VERSION 5.7 ;
BUSBITCHARS "[]" ;
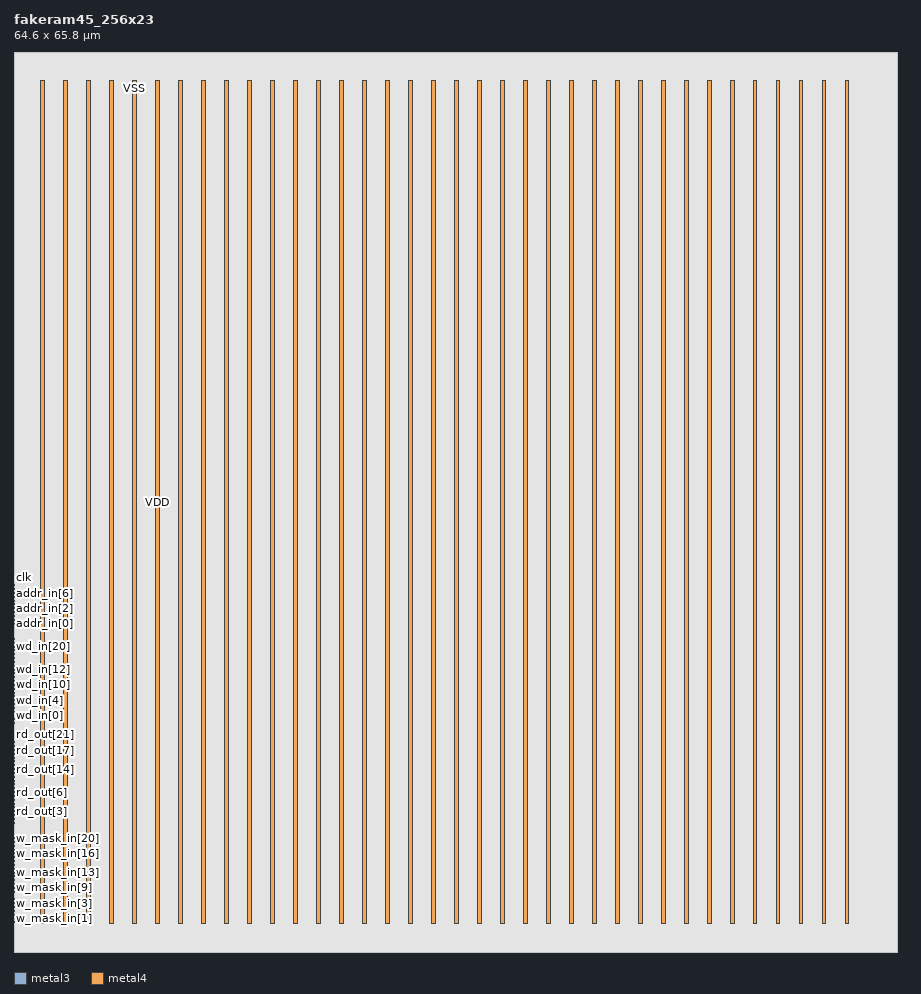
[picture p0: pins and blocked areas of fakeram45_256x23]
MACRO fakeram45_256x23
  FOREIGN fakeram45_256x23 0 0 ;
  SYMMETRY X Y R90 ;
  SIZE 64.600 BY 65.800 ;
  CLASS BLOCK ;
  PIN w_mask_in[0]
    DIRECTION INPUT ;
    USE SIGNAL ;
    SHAPE ABUTMENT ;
    PORT
      LAYER metal3 ;
      RECT 0.000 2.135 0.070 2.205 ;
    END
  END w_mask_in[0]
  PIN w_mask_in[1]
    DIRECTION INPUT ;
    USE SIGNAL ;
    SHAPE ABUTMENT ;
    PORT
      LAYER metal3 ;
      RECT 0.000 2.415 0.070 2.485 ;
    END
  END w_mask_in[1]
  PIN w_mask_in[2]
    DIRECTION INPUT ;
    USE SIGNAL ;
    SHAPE ABUTMENT ;
    PORT
      LAYER metal3 ;
      RECT 0.000 2.695 0.070 2.765 ;
    END
  END w_mask_in[2]
  PIN w_mask_in[3]
    DIRECTION INPUT ;
    USE SIGNAL ;
    SHAPE ABUTMENT ;
    PORT
      LAYER metal3 ;
      RECT 0.000 2.975 0.070 3.045 ;
    END
  END w_mask_in[3]
  PIN w_mask_in[4]
    DIRECTION INPUT ;
    USE SIGNAL ;
    SHAPE ABUTMENT ;
    PORT
      LAYER metal3 ;
      RECT 0.000 3.255 0.070 3.325 ;
    END
  END w_mask_in[4]
  PIN w_mask_in[5]
    DIRECTION INPUT ;
    USE SIGNAL ;
    SHAPE ABUTMENT ;
    PORT
      LAYER metal3 ;
      RECT 0.000 3.535 0.070 3.605 ;
    END
  END w_mask_in[5]
  PIN w_mask_in[6]
    DIRECTION INPUT ;
    USE SIGNAL ;
    SHAPE ABUTMENT ;
    PORT
      LAYER metal3 ;
      RECT 0.000 3.815 0.070 3.885 ;
    END
  END w_mask_in[6]
  PIN w_mask_in[7]
    DIRECTION INPUT ;
    USE SIGNAL ;
    SHAPE ABUTMENT ;
    PORT
      LAYER metal3 ;
      RECT 0.000 4.095 0.070 4.165 ;
    END
  END w_mask_in[7]
  PIN w_mask_in[8]
    DIRECTION INPUT ;
    USE SIGNAL ;
    SHAPE ABUTMENT ;
    PORT
      LAYER metal3 ;
      RECT 0.000 4.375 0.070 4.445 ;
    END
  END w_mask_in[8]
  PIN w_mask_in[9]
    DIRECTION INPUT ;
    USE SIGNAL ;
    SHAPE ABUTMENT ;
    PORT
      LAYER metal3 ;
      RECT 0.000 4.655 0.070 4.725 ;
    END
  END w_mask_in[9]
  PIN w_mask_in[10]
    DIRECTION INPUT ;
    USE SIGNAL ;
    SHAPE ABUTMENT ;
    PORT
      LAYER metal3 ;
      RECT 0.000 4.935 0.070 5.005 ;
    END
  END w_mask_in[10]
  PIN w_mask_in[11]
    DIRECTION INPUT ;
    USE SIGNAL ;
    SHAPE ABUTMENT ;
    PORT
      LAYER metal3 ;
      RECT 0.000 5.215 0.070 5.285 ;
    END
  END w_mask_in[11]
  PIN w_mask_in[12]
    DIRECTION INPUT ;
    USE SIGNAL ;
    SHAPE ABUTMENT ;
    PORT
      LAYER metal3 ;
      RECT 0.000 5.495 0.070 5.565 ;
    END
  END w_mask_in[12]
  PIN w_mask_in[13]
    DIRECTION INPUT ;
    USE SIGNAL ;
    SHAPE ABUTMENT ;
    PORT
      LAYER metal3 ;
      RECT 0.000 5.775 0.070 5.845 ;
    END
  END w_mask_in[13]
  PIN w_mask_in[14]
    DIRECTION INPUT ;
    USE SIGNAL ;
    SHAPE ABUTMENT ;
    PORT
      LAYER metal3 ;
      RECT 0.000 6.055 0.070 6.125 ;
    END
  END w_mask_in[14]
  PIN w_mask_in[15]
    DIRECTION INPUT ;
    USE SIGNAL ;
    SHAPE ABUTMENT ;
    PORT
      LAYER metal3 ;
      RECT 0.000 6.335 0.070 6.405 ;
    END
  END w_mask_in[15]
  PIN w_mask_in[16]
    DIRECTION INPUT ;
    USE SIGNAL ;
    SHAPE ABUTMENT ;
    PORT
      LAYER metal3 ;
      RECT 0.000 6.615 0.070 6.685 ;
    END
  END w_mask_in[16]
  PIN w_mask_in[17]
    DIRECTION INPUT ;
    USE SIGNAL ;
    SHAPE ABUTMENT ;
    PORT
      LAYER metal3 ;
      RECT 0.000 6.895 0.070 6.965 ;
    END
  END w_mask_in[17]
  PIN w_mask_in[18]
    DIRECTION INPUT ;
    USE SIGNAL ;
    SHAPE ABUTMENT ;
    PORT
      LAYER metal3 ;
      RECT 0.000 7.175 0.070 7.245 ;
    END
  END w_mask_in[18]
  PIN w_mask_in[19]
    DIRECTION INPUT ;
    USE SIGNAL ;
    SHAPE ABUTMENT ;
    PORT
      LAYER metal3 ;
      RECT 0.000 7.455 0.070 7.525 ;
    END
  END w_mask_in[19]
  PIN w_mask_in[20]
    DIRECTION INPUT ;
    USE SIGNAL ;
    SHAPE ABUTMENT ;
    PORT
      LAYER metal3 ;
      RECT 0.000 7.735 0.070 7.805 ;
    END
  END w_mask_in[20]
  PIN w_mask_in[21]
    DIRECTION INPUT ;
    USE SIGNAL ;
    SHAPE ABUTMENT ;
    PORT
      LAYER metal3 ;
      RECT 0.000 8.015 0.070 8.085 ;
    END
  END w_mask_in[21]
  PIN w_mask_in[22]
    DIRECTION INPUT ;
    USE SIGNAL ;
    SHAPE ABUTMENT ;
    PORT
      LAYER metal3 ;
      RECT 0.000 8.295 0.070 8.365 ;
    END
  END w_mask_in[22]
  PIN rd_out[0]
    DIRECTION OUTPUT ;
    USE SIGNAL ;
    SHAPE ABUTMENT ;
    PORT
      LAYER metal3 ;
      RECT 0.000 9.415 0.070 9.485 ;
    END
  END rd_out[0]
  PIN rd_out[1]
    DIRECTION OUTPUT ;
    USE SIGNAL ;
    SHAPE ABUTMENT ;
    PORT
      LAYER metal3 ;
      RECT 0.000 9.695 0.070 9.765 ;
    END
  END rd_out[1]
  PIN rd_out[2]
    DIRECTION OUTPUT ;
    USE SIGNAL ;
    SHAPE ABUTMENT ;
    PORT
      LAYER metal3 ;
      RECT 0.000 9.975 0.070 10.045 ;
    END
  END rd_out[2]
  PIN rd_out[3]
    DIRECTION OUTPUT ;
    USE SIGNAL ;
    SHAPE ABUTMENT ;
    PORT
      LAYER metal3 ;
      RECT 0.000 10.255 0.070 10.325 ;
    END
  END rd_out[3]
  PIN rd_out[4]
    DIRECTION OUTPUT ;
    USE SIGNAL ;
    SHAPE ABUTMENT ;
    PORT
      LAYER metal3 ;
      RECT 0.000 10.535 0.070 10.605 ;
    END
  END rd_out[4]
  PIN rd_out[5]
    DIRECTION OUTPUT ;
    USE SIGNAL ;
    SHAPE ABUTMENT ;
    PORT
      LAYER metal3 ;
      RECT 0.000 10.815 0.070 10.885 ;
    END
  END rd_out[5]
  PIN rd_out[6]
    DIRECTION OUTPUT ;
    USE SIGNAL ;
    SHAPE ABUTMENT ;
    PORT
      LAYER metal3 ;
      RECT 0.000 11.095 0.070 11.165 ;
    END
  END rd_out[6]
  PIN rd_out[7]
    DIRECTION OUTPUT ;
    USE SIGNAL ;
    SHAPE ABUTMENT ;
    PORT
      LAYER metal3 ;
      RECT 0.000 11.375 0.070 11.445 ;
    END
  END rd_out[7]
  PIN rd_out[8]
    DIRECTION OUTPUT ;
    USE SIGNAL ;
    SHAPE ABUTMENT ;
    PORT
      LAYER metal3 ;
      RECT 0.000 11.655 0.070 11.725 ;
    END
  END rd_out[8]
  PIN rd_out[9]
    DIRECTION OUTPUT ;
    USE SIGNAL ;
    SHAPE ABUTMENT ;
    PORT
      LAYER metal3 ;
      RECT 0.000 11.935 0.070 12.005 ;
    END
  END rd_out[9]
  PIN rd_out[10]
    DIRECTION OUTPUT ;
    USE SIGNAL ;
    SHAPE ABUTMENT ;
    PORT
      LAYER metal3 ;
      RECT 0.000 12.215 0.070 12.285 ;
    END
  END rd_out[10]
  PIN rd_out[11]
    DIRECTION OUTPUT ;
    USE SIGNAL ;
    SHAPE ABUTMENT ;
    PORT
      LAYER metal3 ;
      RECT 0.000 12.495 0.070 12.565 ;
    END
  END rd_out[11]
  PIN rd_out[12]
    DIRECTION OUTPUT ;
    USE SIGNAL ;
    SHAPE ABUTMENT ;
    PORT
      LAYER metal3 ;
      RECT 0.000 12.775 0.070 12.845 ;
    END
  END rd_out[12]
  PIN rd_out[13]
    DIRECTION OUTPUT ;
    USE SIGNAL ;
    SHAPE ABUTMENT ;
    PORT
      LAYER metal3 ;
      RECT 0.000 13.055 0.070 13.125 ;
    END
  END rd_out[13]
  PIN rd_out[14]
    DIRECTION OUTPUT ;
    USE SIGNAL ;
    SHAPE ABUTMENT ;
    PORT
      LAYER metal3 ;
      RECT 0.000 13.335 0.070 13.405 ;
    END
  END rd_out[14]
  PIN rd_out[15]
    DIRECTION OUTPUT ;
    USE SIGNAL ;
    SHAPE ABUTMENT ;
    PORT
      LAYER metal3 ;
      RECT 0.000 13.615 0.070 13.685 ;
    END
  END rd_out[15]
  PIN rd_out[16]
    DIRECTION OUTPUT ;
    USE SIGNAL ;
    SHAPE ABUTMENT ;
    PORT
      LAYER metal3 ;
      RECT 0.000 13.895 0.070 13.965 ;
    END
  END rd_out[16]
  PIN rd_out[17]
    DIRECTION OUTPUT ;
    USE SIGNAL ;
    SHAPE ABUTMENT ;
    PORT
      LAYER metal3 ;
      RECT 0.000 14.175 0.070 14.245 ;
    END
  END rd_out[17]
  PIN rd_out[18]
    DIRECTION OUTPUT ;
    USE SIGNAL ;
    SHAPE ABUTMENT ;
    PORT
      LAYER metal3 ;
      RECT 0.000 14.455 0.070 14.525 ;
    END
  END rd_out[18]
  PIN rd_out[19]
    DIRECTION OUTPUT ;
    USE SIGNAL ;
    SHAPE ABUTMENT ;
    PORT
      LAYER metal3 ;
      RECT 0.000 14.735 0.070 14.805 ;
    END
  END rd_out[19]
  PIN rd_out[20]
    DIRECTION OUTPUT ;
    USE SIGNAL ;
    SHAPE ABUTMENT ;
    PORT
      LAYER metal3 ;
      RECT 0.000 15.015 0.070 15.085 ;
    END
  END rd_out[20]
  PIN rd_out[21]
    DIRECTION OUTPUT ;
    USE SIGNAL ;
    SHAPE ABUTMENT ;
    PORT
      LAYER metal3 ;
      RECT 0.000 15.295 0.070 15.365 ;
    END
  END rd_out[21]
  PIN rd_out[22]
    DIRECTION OUTPUT ;
    USE SIGNAL ;
    SHAPE ABUTMENT ;
    PORT
      LAYER metal3 ;
      RECT 0.000 15.575 0.070 15.645 ;
    END
  END rd_out[22]
  PIN wd_in[0]
    DIRECTION INPUT ;
    USE SIGNAL ;
    SHAPE ABUTMENT ;
    PORT
      LAYER metal3 ;
      RECT 0.000 16.695 0.070 16.765 ;
    END
  END wd_in[0]
  PIN wd_in[1]
    DIRECTION INPUT ;
    USE SIGNAL ;
    SHAPE ABUTMENT ;
    PORT
      LAYER metal3 ;
      RECT 0.000 16.975 0.070 17.045 ;
    END
  END wd_in[1]
  PIN wd_in[2]
    DIRECTION INPUT ;
    USE SIGNAL ;
    SHAPE ABUTMENT ;
    PORT
      LAYER metal3 ;
      RECT 0.000 17.255 0.070 17.325 ;
    END
  END wd_in[2]
  PIN wd_in[3]
    DIRECTION INPUT ;
    USE SIGNAL ;
    SHAPE ABUTMENT ;
    PORT
      LAYER metal3 ;
      RECT 0.000 17.535 0.070 17.605 ;
    END
  END wd_in[3]
  PIN wd_in[4]
    DIRECTION INPUT ;
    USE SIGNAL ;
    SHAPE ABUTMENT ;
    PORT
      LAYER metal3 ;
      RECT 0.000 17.815 0.070 17.885 ;
    END
  END wd_in[4]
  PIN wd_in[5]
    DIRECTION INPUT ;
    USE SIGNAL ;
    SHAPE ABUTMENT ;
    PORT
      LAYER metal3 ;
      RECT 0.000 18.095 0.070 18.165 ;
    END
  END wd_in[5]
  PIN wd_in[6]
    DIRECTION INPUT ;
    USE SIGNAL ;
    SHAPE ABUTMENT ;
    PORT
      LAYER metal3 ;
      RECT 0.000 18.375 0.070 18.445 ;
    END
  END wd_in[6]
  PIN wd_in[7]
    DIRECTION INPUT ;
    USE SIGNAL ;
    SHAPE ABUTMENT ;
    PORT
      LAYER metal3 ;
      RECT 0.000 18.655 0.070 18.725 ;
    END
  END wd_in[7]
  PIN wd_in[8]
    DIRECTION INPUT ;
    USE SIGNAL ;
    SHAPE ABUTMENT ;
    PORT
      LAYER metal3 ;
      RECT 0.000 18.935 0.070 19.005 ;
    END
  END wd_in[8]
  PIN wd_in[9]
    DIRECTION INPUT ;
    USE SIGNAL ;
    SHAPE ABUTMENT ;
    PORT
      LAYER metal3 ;
      RECT 0.000 19.215 0.070 19.285 ;
    END
  END wd_in[9]
  PIN wd_in[10]
    DIRECTION INPUT ;
    USE SIGNAL ;
    SHAPE ABUTMENT ;
    PORT
      LAYER metal3 ;
      RECT 0.000 19.495 0.070 19.565 ;
    END
  END wd_in[10]
  PIN wd_in[11]
    DIRECTION INPUT ;
    USE SIGNAL ;
    SHAPE ABUTMENT ;
    PORT
      LAYER metal3 ;
      RECT 0.000 19.775 0.070 19.845 ;
    END
  END wd_in[11]
  PIN wd_in[12]
    DIRECTION INPUT ;
    USE SIGNAL ;
    SHAPE ABUTMENT ;
    PORT
      LAYER metal3 ;
      RECT 0.000 20.055 0.070 20.125 ;
    END
  END wd_in[12]
  PIN wd_in[13]
    DIRECTION INPUT ;
    USE SIGNAL ;
    SHAPE ABUTMENT ;
    PORT
      LAYER metal3 ;
      RECT 0.000 20.335 0.070 20.405 ;
    END
  END wd_in[13]
  PIN wd_in[14]
    DIRECTION INPUT ;
    USE SIGNAL ;
    SHAPE ABUTMENT ;
    PORT
      LAYER metal3 ;
      RECT 0.000 20.615 0.070 20.685 ;
    END
  END wd_in[14]
  PIN wd_in[15]
    DIRECTION INPUT ;
    USE SIGNAL ;
    SHAPE ABUTMENT ;
    PORT
      LAYER metal3 ;
      RECT 0.000 20.895 0.070 20.965 ;
    END
  END wd_in[15]
  PIN wd_in[16]
    DIRECTION INPUT ;
    USE SIGNAL ;
    SHAPE ABUTMENT ;
    PORT
      LAYER metal3 ;
      RECT 0.000 21.175 0.070 21.245 ;
    END
  END wd_in[16]
  PIN wd_in[17]
    DIRECTION INPUT ;
    USE SIGNAL ;
    SHAPE ABUTMENT ;
    PORT
      LAYER metal3 ;
      RECT 0.000 21.455 0.070 21.525 ;
    END
  END wd_in[17]
  PIN wd_in[18]
    DIRECTION INPUT ;
    USE SIGNAL ;
    SHAPE ABUTMENT ;
    PORT
      LAYER metal3 ;
      RECT 0.000 21.735 0.070 21.805 ;
    END
  END wd_in[18]
  PIN wd_in[19]
    DIRECTION INPUT ;
    USE SIGNAL ;
    SHAPE ABUTMENT ;
    PORT
      LAYER metal3 ;
      RECT 0.000 22.015 0.070 22.085 ;
    END
  END wd_in[19]
  PIN wd_in[20]
    DIRECTION INPUT ;
    USE SIGNAL ;
    SHAPE ABUTMENT ;
    PORT
      LAYER metal3 ;
      RECT 0.000 22.295 0.070 22.365 ;
    END
  END wd_in[20]
  PIN wd_in[21]
    DIRECTION INPUT ;
    USE SIGNAL ;
    SHAPE ABUTMENT ;
    PORT
      LAYER metal3 ;
      RECT 0.000 22.575 0.070 22.645 ;
    END
  END wd_in[21]
  PIN wd_in[22]
    DIRECTION INPUT ;
    USE SIGNAL ;
    SHAPE ABUTMENT ;
    PORT
      LAYER metal3 ;
      RECT 0.000 22.855 0.070 22.925 ;
    END
  END wd_in[22]
  PIN addr_in[0]
    DIRECTION INPUT ;
    USE SIGNAL ;
    SHAPE ABUTMENT ;
    PORT
      LAYER metal3 ;
      RECT 0.000 23.975 0.070 24.045 ;
    END
  END addr_in[0]
  PIN addr_in[1]
    DIRECTION INPUT ;
    USE SIGNAL ;
    SHAPE ABUTMENT ;
    PORT
      LAYER metal3 ;
      RECT 0.000 24.255 0.070 24.325 ;
    END
  END addr_in[1]
  PIN addr_in[2]
    DIRECTION INPUT ;
    USE SIGNAL ;
    SHAPE ABUTMENT ;
    PORT
      LAYER metal3 ;
      RECT 0.000 24.535 0.070 24.605 ;
    END
  END addr_in[2]
  PIN addr_in[3]
    DIRECTION INPUT ;
    USE SIGNAL ;
    SHAPE ABUTMENT ;
    PORT
      LAYER metal3 ;
      RECT 0.000 24.815 0.070 24.885 ;
    END
  END addr_in[3]
  PIN addr_in[4]
    DIRECTION INPUT ;
    USE SIGNAL ;
    SHAPE ABUTMENT ;
    PORT
      LAYER metal3 ;
      RECT 0.000 25.095 0.070 25.165 ;
    END
  END addr_in[4]
  PIN addr_in[5]
    DIRECTION INPUT ;
    USE SIGNAL ;
    SHAPE ABUTMENT ;
    PORT
      LAYER metal3 ;
      RECT 0.000 25.375 0.070 25.445 ;
    END
  END addr_in[5]
  PIN addr_in[6]
    DIRECTION INPUT ;
    USE SIGNAL ;
    SHAPE ABUTMENT ;
    PORT
      LAYER metal3 ;
      RECT 0.000 25.655 0.070 25.725 ;
    END
  END addr_in[6]
  PIN addr_in[7]
    DIRECTION INPUT ;
    USE SIGNAL ;
    SHAPE ABUTMENT ;
    PORT
      LAYER metal3 ;
      RECT 0.000 25.935 0.070 26.005 ;
    END
  END addr_in[7]
  PIN we_in
    DIRECTION INPUT ;
    USE SIGNAL ;
    SHAPE ABUTMENT ;
    PORT
      LAYER metal3 ;
      RECT 0.000 26.215 0.070 26.285 ;
    END
  END we_in
  PIN ce_in
    DIRECTION INPUT ;
    USE SIGNAL ;
    SHAPE ABUTMENT ;
    PORT
      LAYER metal3 ;
      RECT 0.000 26.495 0.070 26.565 ;
    END
  END ce_in
  PIN clk
    DIRECTION INPUT ;
    USE SIGNAL ;
    SHAPE ABUTMENT ;
    PORT
      LAYER metal3 ;
      RECT 0.000 26.775 0.070 26.845 ;
    END
  END clk
  PIN VSS
    DIRECTION INOUT ;
    USE GROUND ;
    PORT
      LAYER metal4 ;
      RECT 1.960 2.100 2.240 63.700 ;
      RECT 5.320 2.100 5.600 63.700 ;
      RECT 8.680 2.100 8.960 63.700 ;
      RECT 12.040 2.100 12.320 63.700 ;
      RECT 15.400 2.100 15.680 63.700 ;
      RECT 18.760 2.100 19.040 63.700 ;
      RECT 22.120 2.100 22.400 63.700 ;
      RECT 25.480 2.100 25.760 63.700 ;
      RECT 28.840 2.100 29.120 63.700 ;
      RECT 32.200 2.100 32.480 63.700 ;
      RECT 35.560 2.100 35.840 63.700 ;
      RECT 38.920 2.100 39.200 63.700 ;
      RECT 42.280 2.100 42.560 63.700 ;
      RECT 45.640 2.100 45.920 63.700 ;
      RECT 49.000 2.100 49.280 63.700 ;
      RECT 52.360 2.100 52.640 63.700 ;
      RECT 55.720 2.100 56.000 63.700 ;
      RECT 59.080 2.100 59.360 63.700 ;
    END
  END VSS
  PIN VDD
    DIRECTION INOUT ;
    USE POWER ;
    PORT
      LAYER metal4 ;
      RECT 3.640 2.100 3.920 63.700 ;
      RECT 7.000 2.100 7.280 63.700 ;
      RECT 10.360 2.100 10.640 63.700 ;
      RECT 13.720 2.100 14.000 63.700 ;
      RECT 17.080 2.100 17.360 63.700 ;
      RECT 20.440 2.100 20.720 63.700 ;
      RECT 23.800 2.100 24.080 63.700 ;
      RECT 27.160 2.100 27.440 63.700 ;
      RECT 30.520 2.100 30.800 63.700 ;
      RECT 33.880 2.100 34.160 63.700 ;
      RECT 37.240 2.100 37.520 63.700 ;
      RECT 40.600 2.100 40.880 63.700 ;
      RECT 43.960 2.100 44.240 63.700 ;
      RECT 47.320 2.100 47.600 63.700 ;
      RECT 50.680 2.100 50.960 63.700 ;
      RECT 54.040 2.100 54.320 63.700 ;
      RECT 57.400 2.100 57.680 63.700 ;
      RECT 60.760 2.100 61.040 63.700 ;
    END
  END VDD
  OBS
    LAYER metal1 ;
    RECT 0 0 64.600 65.800 ;
    LAYER metal2 ;
    RECT 0 0 64.600 65.800 ;
    LAYER metal3 ;
    RECT 0.070 0 64.600 65.800 ;
    RECT 0 0.000 0.070 2.070 ;
    RECT 0 2.270 0.070 2.350 ;
    RECT 0 2.550 0.070 2.630 ;
    RECT 0 2.830 0.070 2.910 ;
    RECT 0 3.110 0.070 3.190 ;
    RECT 0 3.390 0.070 3.470 ;
    RECT 0 3.670 0.070 3.750 ;
    RECT 0 3.950 0.070 4.030 ;
    RECT 0 4.230 0.070 4.310 ;
    RECT 0 4.510 0.070 4.590 ;
    RECT 0 4.790 0.070 4.870 ;
    RECT 0 5.070 0.070 5.150 ;
    RECT 0 5.350 0.070 5.430 ;
    RECT 0 5.630 0.070 5.710 ;
    RECT 0 5.910 0.070 5.990 ;
    RECT 0 6.190 0.070 6.270 ;
    RECT 0 6.470 0.070 6.550 ;
    RECT 0 6.750 0.070 6.830 ;
    RECT 0 7.030 0.070 7.110 ;
    RECT 0 7.310 0.070 7.390 ;
    RECT 0 7.590 0.070 7.670 ;
    RECT 0 7.870 0.070 7.950 ;
    RECT 0 8.150 0.070 8.230 ;
    RECT 0 8.430 0.070 9.350 ;
    RECT 0 9.550 0.070 9.630 ;
    RECT 0 9.830 0.070 9.910 ;
    RECT 0 10.110 0.070 10.190 ;
    RECT 0 10.390 0.070 10.470 ;
    RECT 0 10.670 0.070 10.750 ;
    RECT 0 10.950 0.070 11.030 ;
    RECT 0 11.230 0.070 11.310 ;
    RECT 0 11.510 0.070 11.590 ;
    RECT 0 11.790 0.070 11.870 ;
    RECT 0 12.070 0.070 12.150 ;
    RECT 0 12.350 0.070 12.430 ;
    RECT 0 12.630 0.070 12.710 ;
    RECT 0 12.910 0.070 12.990 ;
    RECT 0 13.190 0.070 13.270 ;
    RECT 0 13.470 0.070 13.550 ;
    RECT 0 13.750 0.070 13.830 ;
    RECT 0 14.030 0.070 14.110 ;
    RECT 0 14.310 0.070 14.390 ;
    RECT 0 14.590 0.070 14.670 ;
    RECT 0 14.870 0.070 14.950 ;
    RECT 0 15.150 0.070 15.230 ;
    RECT 0 15.430 0.070 15.510 ;
    RECT 0 15.710 0.070 16.630 ;
    RECT 0 16.830 0.070 16.910 ;
    RECT 0 17.110 0.070 17.190 ;
    RECT 0 17.390 0.070 17.470 ;
    RECT 0 17.670 0.070 17.750 ;
    RECT 0 17.950 0.070 18.030 ;
    RECT 0 18.230 0.070 18.310 ;
    RECT 0 18.510 0.070 18.590 ;
    RECT 0 18.790 0.070 18.870 ;
    RECT 0 19.070 0.070 19.150 ;
    RECT 0 19.350 0.070 19.430 ;
    RECT 0 19.630 0.070 19.710 ;
    RECT 0 19.910 0.070 19.990 ;
    RECT 0 20.190 0.070 20.270 ;
    RECT 0 20.470 0.070 20.550 ;
    RECT 0 20.750 0.070 20.830 ;
    RECT 0 21.030 0.070 21.110 ;
    RECT 0 21.310 0.070 21.390 ;
    RECT 0 21.590 0.070 21.670 ;
    RECT 0 21.870 0.070 21.950 ;
    RECT 0 22.150 0.070 22.230 ;
    RECT 0 22.430 0.070 22.510 ;
    RECT 0 22.710 0.070 22.790 ;
    RECT 0 22.990 0.070 23.910 ;
    RECT 0 24.110 0.070 24.190 ;
    RECT 0 24.390 0.070 24.470 ;
    RECT 0 24.670 0.070 24.750 ;
    RECT 0 24.950 0.070 25.030 ;
    RECT 0 25.230 0.070 25.310 ;
    RECT 0 25.510 0.070 25.590 ;
    RECT 0 25.790 0.070 25.870 ;
    RECT 0 26.070 0.070 26.150 ;
    RECT 0 26.350 0.070 26.430 ;
    RECT 0 26.630 0.070 26.710 ;
    RECT 0 26.910 0.070 65.800 ;
    LAYER metal4 ;
    RECT 0 0 64.600 2.100 ;
    RECT 0 63.700 64.600 65.800 ;
    RECT 0.000 2.100 1.960 63.700 ;
    RECT 2.240 2.100 3.640 63.700 ;
    RECT 3.920 2.100 5.320 63.700 ;
    RECT 5.600 2.100 7.000 63.700 ;
    RECT 7.280 2.100 8.680 63.700 ;
    RECT 8.960 2.100 10.360 63.700 ;
    RECT 10.640 2.100 12.040 63.700 ;
    RECT 12.320 2.100 13.720 63.700 ;
    RECT 14.000 2.100 15.400 63.700 ;
    RECT 15.680 2.100 17.080 63.700 ;
    RECT 17.360 2.100 18.760 63.700 ;
    RECT 19.040 2.100 20.440 63.700 ;
    RECT 20.720 2.100 22.120 63.700 ;
    RECT 22.400 2.100 23.800 63.700 ;
    RECT 24.080 2.100 25.480 63.700 ;
    RECT 25.760 2.100 27.160 63.700 ;
    RECT 27.440 2.100 28.840 63.700 ;
    RECT 29.120 2.100 30.520 63.700 ;
    RECT 30.800 2.100 32.200 63.700 ;
    RECT 32.480 2.100 33.880 63.700 ;
    RECT 34.160 2.100 35.560 63.700 ;
    RECT 35.840 2.100 37.240 63.700 ;
    RECT 37.520 2.100 38.920 63.700 ;
    RECT 39.200 2.100 40.600 63.700 ;
    RECT 40.880 2.100 42.280 63.700 ;
    RECT 42.560 2.100 43.960 63.700 ;
    RECT 44.240 2.100 45.640 63.700 ;
    RECT 45.920 2.100 47.320 63.700 ;
    RECT 47.600 2.100 49.000 63.700 ;
    RECT 49.280 2.100 50.680 63.700 ;
    RECT 50.960 2.100 52.360 63.700 ;
    RECT 52.640 2.100 54.040 63.700 ;
    RECT 54.320 2.100 55.720 63.700 ;
    RECT 56.000 2.100 57.400 63.700 ;
    RECT 57.680 2.100 59.080 63.700 ;
    RECT 59.360 2.100 60.760 63.700 ;
    RECT 61.040 2.100 64.600 63.700 ;
    LAYER OVERLAP ;
    RECT 0 0 64.600 65.800 ;
  END
END fakeram45_256x23

END LIBRARY
